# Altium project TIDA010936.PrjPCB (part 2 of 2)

## Sheet TIDA010936_PoL_E1SchDoc.SchDoc
size 431 x 279 mm; Date: Not shown in title block; ApprovedBy: Not shown in title block; CheckedBy: Not shown in title block; Author: Not shown in title block; CompanyName: Not shown in title block; Engineer: Not shown in title block; Organization: Not shown in title block; Address1: Not shown in title block; Address2: Not shown in title block; Address3: Not shown in title block; Address4: Not shown in title block; DocumentNumber: 1; Revision: Use project parameter SCH_Rev; SheetNumber: 4; SheetTotal: 5; PageSetup: Record=PageOptions¦CenterHorizontal=True¦CenterVertical=True¦PrintScale=1.00¦XCorrection=1.00¦YCorrection=1.00¦PrintKind=0¦BorderSize=5000000¦LeftOffset=0¦BottomOffset=0¦Orientation=2¦PaperLength=1000¦PaperWidth=1000¦Scale=100¦PaperSource=15¦PrintQuality=600¦MediaType=1¦DitherType=10¦PaperKind=Letter¦PrintScaleMode=1

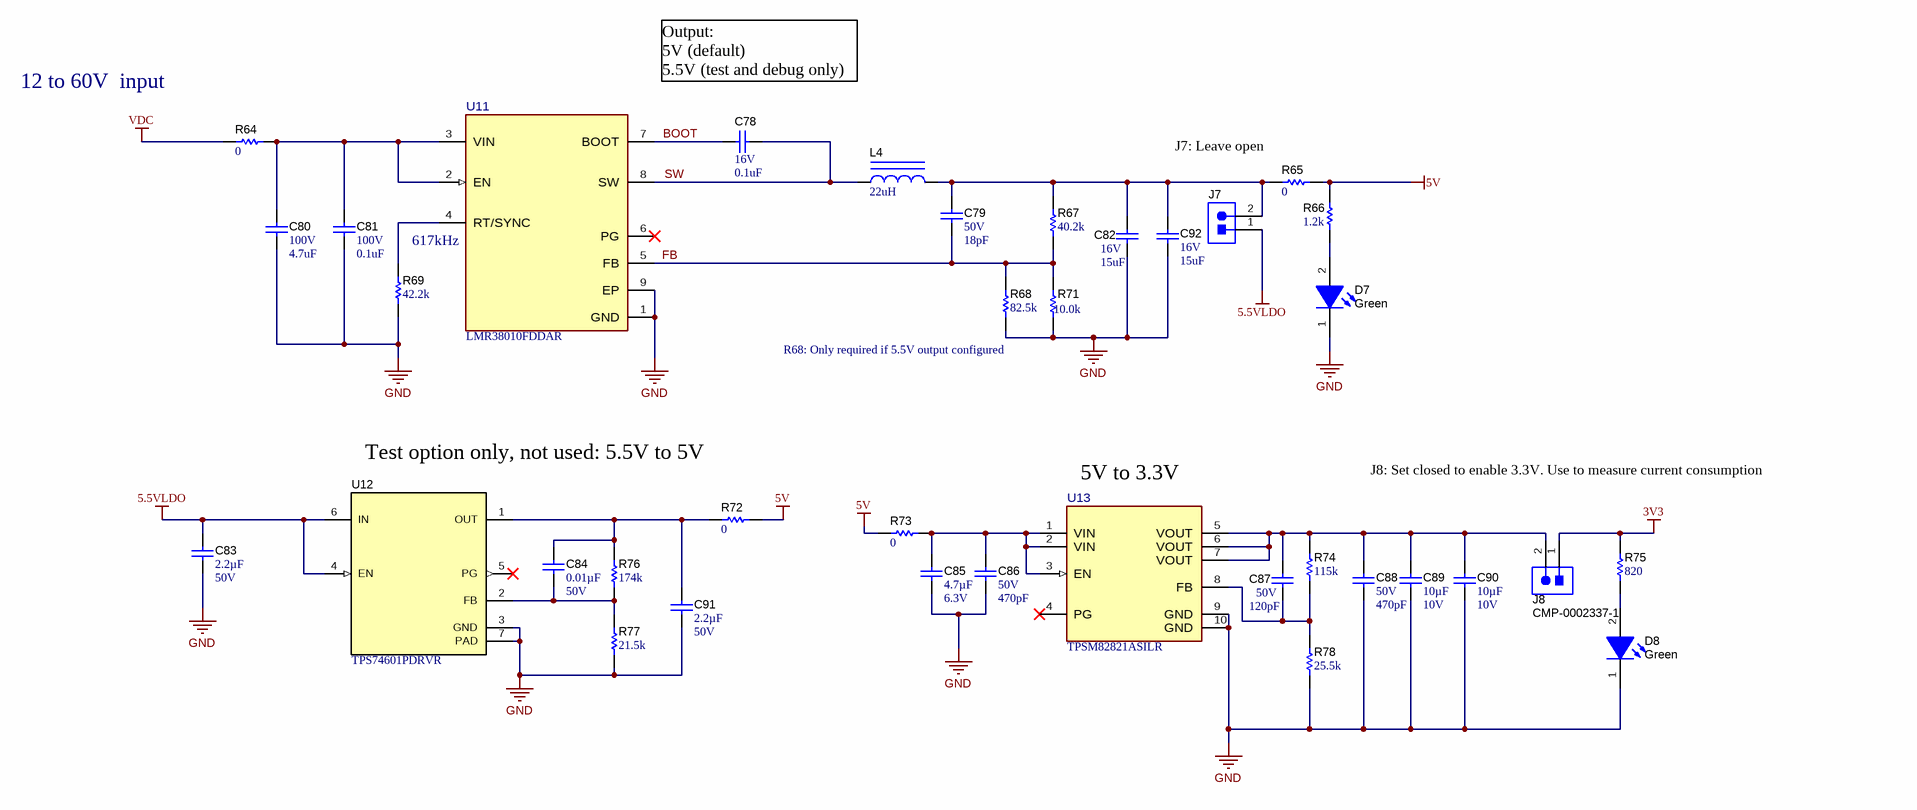
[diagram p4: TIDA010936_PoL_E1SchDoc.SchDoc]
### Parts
C78  VDC_V: 16V  ValueDisplayed: 0.1uF  [0402]  (hidden comment: GRM155R71C104KA88D)
C79  VDC_V: 50V  ValueDisplayed: 18pF  [0402]  (hidden comment: C1005C0G1H180J050BA)
C80  VDC_V: 100V  ValueDisplayed: 4.7uF  [1210]  (hidden comment: C3225X7S2A475K200AE)
C81  VDC_V: 100V  ValueDisplayed: 0.1uF  [0603]  (hidden comment: C1608X7S2A104K080AB)
C82  VDC_V: 16V  ValueDisplayed: 15uF  [0805_HV]  (hidden comment: C2012X6S1C156M125AC)
C83  Cap_F: 2.2µF  VDC_V: 50V  [0805_HV]  (hidden comment: C2012X7R1H225M125AC)
C84  ValueDisplayed: 0.01µF  VDC_V: 50V  [0402]  (hidden comment: CL05B103KB5NNNC)
C85  Cap_F: 4.7µF  VDC_V: 6.3V  [0603]  (hidden comment: JMK107BB7475MA-T)
C86  VDC_V: 50V  ValueDisplayed: 470pF  [0402]  (hidden comment: GCM155R71H471KA37D)
C87  VDC_V: 50V  ValueDisplayed: 120pF  [0402]  (hidden comment: GRM1555C1H121FA01D)
C88  VDC_V: 50V  ValueDisplayed: 470pF  [0402]  (hidden comment: GCM155R71H471KA37D)
C89  Cap_F: 10µF  VDC_V: 10V  [0603]  (hidden comment: GRM188Z71A106MA73D)
C90  Cap_F: 10µF  VDC_V: 10V  [0603]  (hidden comment: GRM188Z71A106MA73D)
C91  Cap_F: 2.2µF  VDC_V: 50V  [0805_HV]  (hidden comment: C2012X7R1H225M125AC)
C92  VDC_V: 16V  ValueDisplayed: 15uF  [0805_HV]  (hidden comment: C2012X6S1C156M125AC)
D7  value Green  [WL-SMCW_GREEN]  (hidden comment: CMP-0002905-2)
D8  value Green  [WL-SMCW_GREEN]  (hidden comment: CMP-0002905-2)
J7  CMP-0002337-1  [CONN_PEC02SAAN]  (value not drawn)
J8  CMP-0002337-1  [CONN_PEC02SAAN]
L4  ValueDisplayed: 22uH  [WE-LHMI_4020]  (hidden comment: 74437324220)
R64  ValueDisplayed: 0  [0603]  (hidden comment: PMR03EZPJ000)
R65  ValueDisplayed: 0  [0603]  (hidden comment: PMR03EZPJ000)
R66  ValueDisplayed: 1.2k  [0402]  (hidden comment: CMP-0026854-5)
R67  ValueDisplayed: 40.2k  [0402]  (hidden comment: CRCW040240K2FKED)
R68  ValueDisplayed: 82.5k  [0603]  (hidden comment: CRCW060382K5FKEA)
R69  ValueDisplayed: 42.2k  [0603]  (hidden comment: CRCW060342K2FKEA)
R71  ValueDisplayed: 10.0k  [0603]  (hidden comment: M55342K12B10E0T)
R72  ValueDisplayed: 0  [0603]  (hidden comment: PMR03EZPJ000)
R73  ValueDisplayed: 0  [0603]  (hidden comment: PMR03EZPJ000)
R74  ValueDisplayed: 115k  [0402]  (hidden comment: CRCW0402115KFKED)
R75  ValueDisplayed: 820  [0402]  (hidden comment: CMP-0026979-3)
R76  ValueDisplayed: 174k  [0402]  (hidden comment: CRCW0402174KFKED)
R77  ValueDisplayed: 21.5k  [0402]  (hidden comment: CRCW040221K5FKED)
R78  ValueDisplayed: 25.5k  [0402]  (hidden comment: CRCW040225K5FKED)
U11  LMR38010FDDAR  [DDA0008E-MFG]
U12  TPS74601PDRVR  [DRV0006A]
U13  TPSM82821ASILR  [SIL0010D-MFG]

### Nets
3V3: J8.1 R75.2
5.5VLDO: C83.1 J7.1 U12.4(EN) U12.6(IN)
5V: R65.1 R66.1 R72.1 R73.2
GND: C80.2 C81.2 C82.2 C83.2 C85.2 C86.2 C88.2 C89.2 C90.2 C91.2 C92.2 D7.1(K) D8.1(K) R68.1 R69.1 R71.1 R77.1 R78.1 U11.1(GND) U11.9(EP) U12.3(GND) U12.7(PAD) U13.9(GND) U13.10(GND)
VDC: R64.2
BOOT: C78.2 U11.7(BOOT)
FB: C79.2 R67.1 R68.2 R71.2 U11.5(FB)
SW: C78.1 L4.1 U11.8(SW)
NetC79_1: C79.1 C82.1 C92.1 J7.2 L4.2 R65.2 R67.2
NetC80_1: C80.1 C81.1 R64.1 U11.2(EN) U11.3(VIN)
NetC84_1: C84.1 C91.1 R72.2 R76.2 U12.1(OUT)
NetC84_2: C84.2 R76.1 R77.2 U12.2(FB)
NetC85_1: C85.1 C86.1 R73.1 U13.1(VIN) U13.2(VIN) U13.3(EN)
NetC87_1: C87.1 C88.1 C89.1 C90.1 J8.2 R74.2 U13.5(VOUT) U13.6(VOUT) U13.7(VOUT)
NetC87_2: C87.2 R74.1 R78.2 U13.8(FB)
NetD7_2: D7.2(A) R66.2
NetD8_2: D8.2(A) R75.1
NetR69_2: R69.2 U11.4(RT/SYNC)

Not connected (* = marked no-connect by the designer): U11 6(PG)*; U12 5(PG)*; U13 4(PG)*

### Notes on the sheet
- 12 to 60V  input
- Output:
  5V (default)
  5.5V (test and debug only)
- (near R65) J7: Leave open
- (near U11) 617kHz
- R68: Only required if 5.5V output configured
- Test option only, not used: 5.5V to 5V
- (near U13) 5V to 3.3V
- J8: Set closed to enable 3.3V. Use to measure current consumption

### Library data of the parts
C78 = CMP-0006641-2: CAP, CERM, 0.1 uF, 16 V, +/- 10%, X7R, 0402; Manufacturer: MuRata; TaMin_C: -55°C; Polarized: N; SizeAreaWB_mm2: 3; Value1: Unknown; U/M: EA; Value: 0.1uF; TaMax_C: 125°C; SizeZ_mm: 0.6; SizeX_mm: 1; SizeY_mm: 0.5; Cap_F: 100nF; AEC Category: Q200
C79 = CMP-0006247-2: CAP, CERM, 18 pF, 50 V, +/- 5%, C0G/NP0, 0402; Manufacturer: TDK; TaMin_C: -55°C; Polarized: N; SizeAreaWB_mm2: 3; Value1: Unknown; U/M: EA; Value: 18pF; TaMax_C: 125°C; SizeZ_mm: 0.6; SizeX_mm: 1; SizeY_mm: 0.5; AEC Category: Q200
C80 = CMP-0009135-2: CAP, CERM, 4.7 uF, 100 V, +/- 10%, X7S, 1210; Manufacturer: TDK; TaMin_C: -55°C; Polarized: N; SizeAreaWB_mm2: 14.7; Value1: Unknown; U/M: EA; Value: 4.7uF; TaMax_C: 125°C; SizeZ_mm: 1.35; SizeX_mm: 3.2; SizeY_mm: 2.5; SizeArea_mm2: 8; Cap_F: 4.7µF; AEC Category: Q200
C81 = CMP-0007059-4: CAP, CERM, 0.1 uF, 100 V, +/- 10%, X7S, 0603; Manufacturer: TDK; TaMin_C: -55°C; ESR_ohm: 49.59m; Polarized: N; SizeAreaWB_mm2: 4.68; Value1: 0.04959 ohm; U/M: EA; Value: 0.1uF; TaMax_C: 125°C; SizeZ_mm: 1; SizeX_mm: 1.6; SizeY_mm: 0.8; SizeArea_mm2: 1.28; Cap_F: 100nF; IRMS_A: 751.618mA; AEC Category: Q200
C82 C92 = CMP-0007851-1: CAP, CERM, 15 uF, 16 V, +/- 20%, X6S, 0805; Manufacturer: TDK; TaMin_C: -55°C; ESR_ohm: 1.669m; Polarized: N; SizeAreaWB_mm2: 6.75; Value1: 0.001669 ohm; U/M: EA; Value: 15uF; TaMax_C: 105°C; SizeZ_mm: 1.45; SizeX_mm: 2; SizeY_mm: 1.25; Cap_Case: 0805; SizeArea_mm2: 2.5; Cap_F: 15µF; IRMS_A: 5.0498A; AEC Category: Q200
C83 C91 = CMP-0007878-2: CAP, CERM, 2.2 uF, 50 V, +/- 20%, X7R, 0805; Manufacturer: TDK; TaMin_C: -55°C; Polarized: N; SizeAreaWB_mm2: 6.75; Value1: Unknown; U/M: EA; Value: 2.2uF; TaMax_C: 125°C; SizeZ_mm: 1.45; SizeX_mm: 2; SizeY_mm: 1.25; Cap_Case: 0805; SizeArea_mm2: 2.5; AEC Category: Q200
C84 = CMP-0860562-1: CAP, CERM, 0.01 µF, 50 V,+/- 10%, X7R, 0402; Manufacturer: Samsung Electro-Mechanics; SizeAreaWB_mm2: 3; Polarized: N; TaMin_C: -55°C; SizeX_mm: 1; AEC Category: Q200; U/M: EA; SizeArea_mm2: 0.5; Cap_F: 10nF; Value: 0.01uF; TaMax_C: 125°C; SizeZ_mm: 0.6
C85 = CMP-0007503-4: CAP, CERM, 4.7 uF, 6.3 V, +/- 10%, X7R, 0603; Manufacturer: Taiyo Yuden; TaMin_C: -55°C; Polarized: N; SizeAreaWB_mm2: 4.68; Value1: Unknown; U/M: EA; Value: 4.7uF; TaMax_C: 125°C; SizeZ_mm: 1; SizeX_mm: 1.6; SizeY_mm: 0.8; SizeArea_mm2: 1.28; AEC Category: Q200
C86 C88 = CMP-0006360-2: CAP, CERM, 470 pF, 50 V, +/- 10%, X7R, AEC-Q200 Grade 1, 0402; Manufacturer: MuRata; TaMin_C: -55°C; Polarized: N; SizeAreaWB_mm2: 3; Value1: Unknown; U/M: EA; Value: 470pF; TaMax_C: 125°C; SizeZ_mm: 0.6; SizeX_mm: 1; SizeY_mm: 0.5; AEC Qualified: Y; AEC Category: Q200
C87 = CMP-0006416-2: CAP, CERM, 120 pF, 50 V, +/- 1%, C0G/NP0, 0402; Manufacturer: MuRata; TaMin_C: -55°C; Polarized: N; SizeAreaWB_mm2: 3; Value1: Unknown; U/M: EA; Value: 120pF; TaMax_C: 125°C; SizeZ_mm: 0.6; SizeX_mm: 1; SizeY_mm: 0.5; AEC Category: Q200
C89 C90 = CMP-0007497-5: CAP, CERM, 10 uF, 10 V, +/- 20%, X7R, 0603; Manufacturer: MuRata; TaMin_C: -55°C; Polarized: N; SizeAreaWB_mm2: 4.68; Value1: Unknown; U/M: EA; Value: 10uF; TaMax_C: 125°C; SizeZ_mm: 1; SizeX_mm: 1.6; SizeY_mm: 0.8; SizeArea_mm2: 1.28; AEC Category: Q200
D7 D8 = CMP-0002905-2: LED, Green, SMD; Manufacturer: Wurth Elektronik; PartNumber: 150060GS75000; Type: InGaN; Vf_V: 3.2V; Io_A: 20mA; Tjmax_C: 85°C; Value1: W; Angle: 140
J7 J8 = CMP-0002337-1: Header, 100mil, 2x1, Tin, TH; PartNumber: PEC02SAAN; Manufacturer: Sullins Connector Solutions; Pitch_mm: 2.54; Gender: Male; Shrouded: N; Row_Count: 1; Current_A: 3A; Voltage_V: 1.8kV; Cert_UL: Y; CNHeader: TRUE; Green_Lifecycle: Not Set; Green_REACh: Incomplete; CT: FALSE
L4 = CMP-0064489-2: Inductor, Shielded Drum Core, Powdered Iron, 22 uH, 1 A, 0.47 ohm, SMD; Manufacturer: Wurth Elektronik; Isat: 2A @ 20% inductance drop; Irms: 1A @ 40C rise; Green_Lifecycle: Active; SizeAreaWB_mm2: 27.577; DCR_ohm: 0.47; Green_REACh: Passed; Value: 22uH; Imax_A: 1A; SizeZ_mm: 2; SizeX_mm: 4.45; SizeY_mm: 4.06; SizeArea_mm2: 18.067; Ind_H: 22µH; AEC Category: Q200
R64 R65 R72 R73 = CMP-0086358-1: RES, 0, 0%, 0.25 W, AEC-Q200 Grade 0, 0603; Manufacturer: Rohm; Power_W: 250mW; SizeZ_mm: 1; SizeArea_mm2: 1.28; Value2: 0.25W; SizeAreaWB_mm2: 4.68; Value_Code: 0000; Value: 0; AEC Qualified: Y; AEC Category: Q200; SizeX_mm: 1.6; SizeY_mm: 0.8
R66 = CMP-0026854-5: RES, 1.2 k, 5%, 0.063 W, AEC-Q200 Grade 0, 0402; PartNumber: CRCW04021K20JNED; Manufacturer: Vishay-Dale; Value: 1.2k; Value_Code: 1k20; Power_W: 63mW; Value2: 0.063W; VDC_V: 50V; TempCo: 200 ppm/C; EIA_Code: E24; AEC Category: Q200; AEC Qualified: Y; AEC Grade: 0; SizeArea_mm2: 0.5; SizeX_mm: 1; SizeZ_mm: 0.6
R67 = CMP-0026367-2: RES, 40.2 k, 1%, 0.063 W, AEC-Q200 Grade 0, 0402; Manufacturer: Vishay-Dale; Power_W: 63mW; TempCo: 100 ppm/C; Value_Code: 40k2; Value: 40.2k; EIA_Code: E96; SizeX_mm: 1; SizeY_mm: 0.5; SizeZ_mm: 0.6; Value2: 0.063W; AEC Qualified: Y; VDC_V: 50V; AEC Category: Q200; AEC Grade: 0
R68 = CMP-0022620-2: RES, 82.5 k, 1%, 0.1 W, 0603; Manufacturer: Vishay-Dale; Power_W: 100mW; TempCo: 100 ppm/C; Value_Code: 82k5; U/M: EA; Value: 82.5k; EIA_Code: E96; SizeX_mm: 1.6; SizeY_mm: 0.8; SizeZ_mm: 1; Value2: 0.1W; SizeArea_mm2: 1.28; VDC_V: 75V; AEC Category: Q200
R69 = CMP-0022418-4: RES, 42.2 k, 1%, 0.1 W, AEC-Q200 Grade 0, 0603; Manufacturer: Vishay-Dale; Power_W: 100mW; TempCo: 100 ppm/C; Value_Code: 42k2; Value: 42.2k; EIA_Code: E96; SizeX_mm: 1.6; SizeY_mm: 0.8; SizeZ_mm: 1; Value2: 0.1W; SizeArea_mm2: 1.28; AEC Qualified: Y; VDC_V: 75V; AEC Category: Q200; AEC Grade: 0
R71 = CMP-0080488-1: RES, 10.0 k, 1%, 0.1 W, 0603; Manufacturer: TT Electronics/IRC; Power_W: 100mW; TempCo: 100 ppm/C; SizeAreaWB_mm2: 4.68; Value_Code: 10k0; Value: 10.0k; EIA_Code: E96; Res_ohm: 10k; SizeX_mm: 1.6; SizeY_mm: 0.8; SizeZ_mm: 1; Value2: 0.1W; SizeArea_mm2: 1.28; AEC Qualified: N; AEC Category: Q200
R74 = CMP-0025971-3: RES, 115 k, 1%, 0.063 W, AEC-Q200 Grade 0, 0402; Manufacturer: Vishay-Dale; Power_W: 63mW; TempCo: 100 ppm/C; Value: 115k; EIA_Code: E96; SizeX_mm: 1; SizeY_mm: 0.5; SizeZ_mm: 0.6; Value2: 0.063W; AEC Qualified: Y; VDC_V: 50V; AEC Category: Q200; AEC Grade: 0
R75 = CMP-0026979-3: RES, 820, 5%, 0.063 W, AEC-Q200 Grade 0, 0402; PartNumber: CRCW0402820RJNED; Manufacturer: Vishay-Dale; Value: 820; Value_Code: 820R; Power_W: 63mW; Value2: 0.063W; VDC_V: 50V; TempCo: 200 ppm/C; EIA_Code: E24; AEC Category: Q200; AEC Qualified: Y; AEC Grade: 0; SizeX_mm: 1; SizeY_mm: 0.5; SizeZ_mm: 0.6
R76 = CMP-0026046-3: RES, 174 k, 1%, 0.063 W, AEC-Q200 Grade 0, 0402; Manufacturer: Vishay-Dale; Power_W: 63mW; TempCo: 100 ppm/C; Value: 174k; EIA_Code: E96; SizeX_mm: 1; SizeY_mm: 0.5; SizeZ_mm: 0.6; Value2: 0.063W; AEC Qualified: Y; VDC_V: 50V; AEC Category: Q200; AEC Grade: 0
R77 = CMP-0026171-2: RES, 21.5 k, 1%, 0.063 W, AEC-Q200 Grade 0, 0402; Manufacturer: Vishay-Dale; Power_W: 63mW; TempCo: 100 ppm/C; Value_Code: 21k5; Value: 21.5k; EIA_Code: E96; SizeX_mm: 1; SizeY_mm: 0.5; SizeZ_mm: 0.6; Value2: 0.063W; AEC Qualified: Y; VDC_V: 50V; AEC Category: Q200; AEC Grade: 0
R78 = CMP-0026201-2: RES, 25.5 k, 1%, 0.063 W, AEC-Q200 Grade 0, 0402; Manufacturer: Vishay-Dale; Power_W: 63mW; TempCo: 100 ppm/C; Value_Code: 25k5; Value: 25.5k; EIA_Code: E96; SizeX_mm: 1; SizeY_mm: 0.5; SizeZ_mm: 0.6; Value2: 0.063W; AEC Qualified: Y; VDC_V: 50V; AEC Category: Q200; AEC Grade: 0
U11 = CMP-0096892-1: 4.2-V to 80-V, 1-A Synchronous Buck Converter with 40-µA IQ; Manufacturer: Texas Instruments; Output Type: AdjustableProgrammable; AEC Qualified: No; Output Voltage: 1-75V; Standoff Height: 0mm; Nominal Supply Current: 40uA; Number Of Outputs: 1; TJmax_C: +150°C; Switching Frequency: 200-2200kHz; Min Supply Voltage: 4.2V; Max Duty Cycle: 97%; Max Supply Voltage: 80V; SizeZ_mm: 1.7mm
U12 = CMP-0085198-1: 1-A LDO With Power-Good, DRV0006A (WSON-6); Alternate Manufacturer: Texas Instruments; SizeX_mm: 2; SizeArea_mm2: 4; AEC Category: Q200; CompType: IC; SizeAreaWB_mm2: 9; AEC Qualified: N; SizeZ_mm: 0.8
U13 = CMP-0092387-1: 1-A High Efficiency Step-Down Converter MicroSiP Power Module with Integrated Inductor; Manufacturer: Texas Instruments; AEC Qualified: No; Min Supply Voltage: 2.4V; Max Supply Voltage: 5.5V; SizeZ_mm: 1.1mm; Nominal Supply Current: 4uA; TJmax_C: +125°C; Max Duty Cycle: 100%; Output Type: AdjustableProgrammable; Switching Frequency: 4MHz; Number Of Outputs: 1; Switching Topology: Buck; Output Voltage: 0.6-4V

## Sheet TIDA010936_Hardware_E1.SchDoc
size 431 x 279 mm; Date: Not shown in title block; ApprovedBy: Not shown in title block; CheckedBy: Not shown in title block; Author: Not shown in title block; CompanyName: Not shown in title block; DrawnBy: e; Engineer: Not shown in title block; Organization: Not shown in title block; Address1: Not shown in title block; Address2: Not shown in title block; Address3: Not shown in title block; Address4: Not shown in title block; DocumentNumber: 3; Revision: Use project parameter SCH_Rev; SheetNumber: 5; SheetTotal: 5; PageSetup: Record=PageOptions¦CenterHorizontal=True¦CenterVertical=True¦PrintScale=1.00¦XCorrection=1.00¦YCorrection=1.00¦PrintKind=0¦BorderSize=5000000¦LeftOffset=0¦BottomOffset=0¦Orientation=2¦PaperLength=1000¦PaperWidth=1000¦Scale=100¦PaperSource=15¦PrintQuality=600¦MediaType=1¦DitherType=10¦PaperKind=Letter¦PrintScaleMode=1

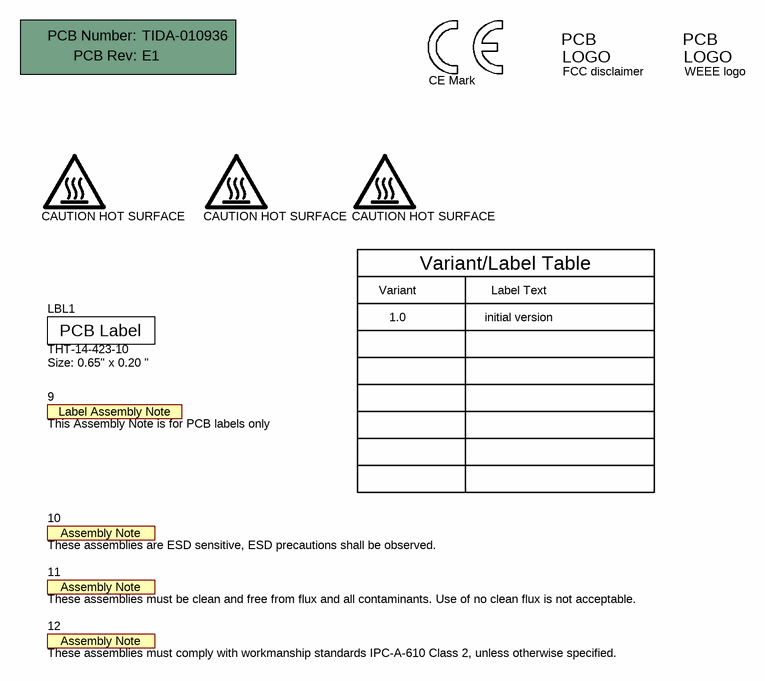
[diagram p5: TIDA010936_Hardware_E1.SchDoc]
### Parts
2  CE Mark  [CE_Mark_5mm]  (no BOM)
4  FCC disclaimer  [FCC_disclaimer]  (no BOM)
5  WEEE logo  [WEEE_Minimum]  (no BOM)
6  CAUTION HOT SURFACE  [IEC_HotSurface_Small]  (no BOM)
7  CAUTION HOT SURFACE  [IEC_HotSurface_Small]  (no BOM)
8  CAUTION HOT SURFACE  [IEC_HotSurface_Small]  (no BOM)
9  This Assembly Note is for PCB labels only  [AssemblyNoteLabel]  (no BOM)
10  These assemblies are ESD sensitive, ESD precautions shall be observed.  [AssemblyNote]  (no BOM)
11  These assemblies must be clean and free from flux and all contaminants. Use of no clean flux is not acceptable.  [AssemblyNote]  (no BOM)
12  These assemblies must comply with workmanship standards IPC-A-610 Class 2, unless otherwise specified.  [AssemblyNote]  (no BOM)
!PCB1  Printed Circuit Board  (value not drawn)  (mechanical)
LBL1  THT-14-423-10  Note: Size: 0.65" x 0.20 "  [Label_650x200]

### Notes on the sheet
- Variant
- Variant/Label Table
- Label Text
- 1.0
- initial version

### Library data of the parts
2 = CMP-0074844-1: SymbolCreator: a0412235
4 = CMP-0074847-1: FCC_disclaimer; Library Reference: Logo
5 = CMP-0074769-3: Manufacturer: Texas Instruments; CompType: IC; AEC Category: Q200
6-8 = CMP-0074837-1: IEC 61010-1 Hot Surface Warning; SymbolCreator: a0412235
9 = CMP-0003616-3
10 = CMP-0077236-1
11 = CMP-0077237-1
12 = CMP-0077238-1
!PCB1 = CMP-0003618-2: Manufacturer: Any; PartNumber: TIDA-010936
LBL1 = CMP-0003625-1: Thermal Transfer Printable Labels, 0.650" W x 0.200" H - 10,000 per roll; Manufacturer: Brady; CompType: Label

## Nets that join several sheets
3V3: TIDA010936_Current_Sense_E1 (8 pins), TIDA010936_Interface_E1 (8 pins), TIDA010936_PoL_E1SchDoc (J8.1 R75.2)
5V: TIDA010936_GaN_E1 (J1.1 R3.1), TIDA010936_Current_Sense_E1 (D1.2), TIDA010936_PoL_E1SchDoc (R65.1 R66.1 R72.1 R73.2)
5VGAN: TIDA010936_GaN_E1 (12 pins), TIDA010936_Current_Sense_E1 (L2.2), TIDA010936_Interface_E1 (R47.1)
AIN+: TIDA010936_GaN_E1 (U1.5), TIDA010936_Current_Sense_E1 (R18.1 R24.2)
AIN-: TIDA010936_Current_Sense_E1 (R18.2 R19.2 R23.2), TIDA010936_Interface_E1 (J5.3)
BIN+: TIDA010936_GaN_E1 (U2.5), TIDA010936_Current_Sense_E1 (R26.1 R30.2)
BIN-: TIDA010936_Current_Sense_E1 (R26.2 R27.2 R31.2), TIDA010936_Interface_E1 (J5.2)
GND: TIDA010936_GaN_E1 (20 pins), TIDA010936_Current_Sense_E1 (33 pins), TIDA010936_Interface_E1 (24 pins), TIDA010936_PoL_E1SchDoc (24 pins)
PGND: TIDA010936_GaN_E1 (32 pins), TIDA010936_Interface_E1 (J6.2 TP5.1)
Test_GND: TIDA010936_GaN_E1 (U3.5), TIDA010936_Current_Sense_E1 (7 pins)
V_BUS: TIDA010936_GaN_E1 (29 pins), TIDA010936_Current_Sense_E1 (R35.2)
VDC: TIDA010936_GaN_E1 (C1.1 R1.1), TIDA010936_Current_Sense_E1 (R20.2 R36.2), TIDA010936_Interface_E1 (J6.1), TIDA010936_PoL_E1SchDoc (R64.2)
DCBUS: TIDA010936_Current_Sense_E1 (C46.1 R20.1 R22.2), TIDA010936_Interface_E1 (R49.1)
IA: TIDA010936_Current_Sense_E1 (U4.5), TIDA010936_Interface_E1 (R54.1)
IB: TIDA010936_Current_Sense_E1 (U6.5), TIDA010936_Interface_E1 (R55.1)
OC: TIDA010936_Current_Sense_E1 (C64.1 R43.1 R44.2), TIDA010936_Interface_E1 (J3.10 U9.12 U10.12)
PWM_AH: TIDA010936_GaN_E1 (R9.2), TIDA010936_Interface_E1 (R58.2 U9.10)
PWM_AL: TIDA010936_GaN_E1 (R11.2), TIDA010936_Interface_E1 (R61.2 U10.10)
PWM_BH: TIDA010936_GaN_E1 (R8.2), TIDA010936_Interface_E1 (R59.2 U9.9)
PWM_BL: TIDA010936_GaN_E1 (R10.2), TIDA010936_Interface_E1 (R62.2 U10.9)
PWM_CH: TIDA010936_GaN_E1 (R16.2), TIDA010936_Interface_E1 (R60.2 U9.8)
PWM_CL: TIDA010936_GaN_E1 (R17.2), TIDA010936_Interface_E1 (R63.2 U10.8)
Temp: TIDA010936_GaN_E1 (R12.1 RT1.2), TIDA010936_Interface_E1 (R57.1)
VA: TIDA010936_Current_Sense_E1 (C44.1 R19.1 R21.2), TIDA010936_Interface_E1 (R50.1)
VB: TIDA010936_Current_Sense_E1 (C52.1 R27.1 R29.2), TIDA010936_Interface_E1 (R51.1)
VC: TIDA010936_Current_Sense_E1 (C63.1 R42.1 R46.2), TIDA010936_Interface_E1 (R53.1)
VC-MOTOR: TIDA010936_Current_Sense_E1 (R39.2 R42.2 R45.2), TIDA010936_Interface_E1 (J5.1)

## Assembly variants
001: not fitted C47 C53 C57 C65 C66 C79 C84 C91 J1 J4 R34 R47 R48 R68 R72 R76 R77 U7 U8 U12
